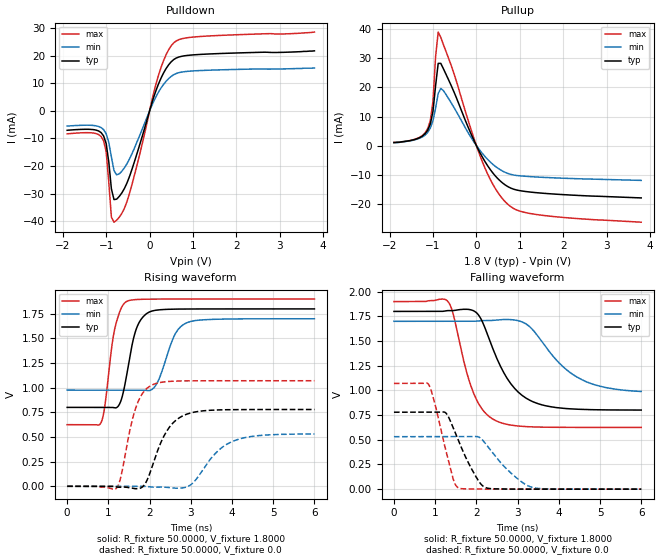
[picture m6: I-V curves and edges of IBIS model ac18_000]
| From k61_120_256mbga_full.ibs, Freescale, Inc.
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|   Model ac18_000
[Model]  ac18_000
Model_type Output
Polarity   Non-Inverting
Enable   Active-High
Vmeas =  0.9000V
Cref =   5.0000pF
Rref =   50.0000
C_comp   2.8000pF   2.5000pF   3.3000pF
[Temperature Range]   25.0000   0.1250k   -40.0000
[Voltage Range]   1.8000V   1.7000V   1.9000V
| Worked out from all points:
|   slope of the pulldown table from 0 to 0.27 V, typ, clamps not added: 22.3 ohm
|   slope of the pullup table from 0 to 0.27 V, typ, clamps not added: 37.5 ohm
|   rising waveform, R_fixture 50.0000, V_fixture 1.8000: 20-80 % time 294ps typ, 374ps min, 247ps max; typ from 0.801 V to 1.8 V
|   rising waveform, R_fixture 50.0000, V_fixture 0.0: 20-80 % time 500ps typ, 675ps min, 357ps max; typ from 0 V to 0.779 V
|   falling waveform, R_fixture 50.0000, V_fixture 1.8000: 20-80 % time 734ps typ, 980ps min, 526ps max; typ from 1.8 V to 0.801 V
|   falling waveform, R_fixture 50.0000, V_fixture 0.0: 20-80 % time 514ps typ, 712ps min, 368ps max; typ from 0.779 V to 0 V
[Pulldown]
|Voltage   I(typ)   I(min)   I(max)
-1.9V     -7.024mA   -5.499mA   -8.317mA
-1.3V     -6.77mA    -5.264mA   -8.01mA
-1.06V    -9.044mA   -6.767mA   -10.8mA
-1V       -11.87mA   -8.293mA   -14.84mA
-880mV    -28.28mA   -16.74mA   -38.55mA
-820mV    -32.16mA   -21.62mA   -40.36mA
-700mV    -31.05mA   -22.85mA   -38.59mA
-520mV    -26.11mA   -19.13mA   -32.84mA
200mV     9.554mA    6.678mA    12.65mA
380mV     15.35mA    10.75mA    20.37mA
560mV     18.67mA    13.17mA    24.75mA
3.8V      21.8mA     15.6mA     28.6mA
[Pullup]
|Voltage   I(typ)   I(min)   I(max)
-1.9V     1mA        1mA        1.1mA
-1.36V    2.38mA     2.23mA     2.47mA
-1.12V    5.32mA     4.56mA     5.88mA
-1.06V    7.48mA     6.04mA     8.7mA
-1V       11.81mA    8.569mA    15.23mA
-940mV    20.56mA    12.89mA    30.55mA
-880mV    28.3mA     17.89mA    39.08mA
-760mV    26.45mA    18.92mA    34.77mA
140mV     -4.031mA   -2.77mA    -5.668mA
680mV     -13.73mA   -9.341mA   -19.61mA
1.4V      -16.26mA   -10.85mA   -23.79mA
3.8V      -18.05mA   -12.01mA   -26.41mA
[Ramp]
| variable   typ   min   max
dV/dt_r  0.4676/0.5001n   0.3185/0.6747n   0.6427/0.3574n
dV/dt_f  0.5993/0.7337n   0.4264/0.9804n   0.7648/0.5257n
R_load = 50.0000
[Rising Waveform]
R_fixture= 50.0000
V_fixture= 1.8000
V_fixture_min= 1.7000
V_fixture_max= 1.9000
|time   V(typ)   V(min)   V(max)
0s        800.8mV    975.9mV    625.4mV
824.9ps   800.7mV    975.9mV    648.2mV
1.157ns   795.6mV    975.9mV    1.601V
1.315ns   879.5mV    975.9mV    1.811V
1.462ns   1.171V     975.9mV    1.879V
1.695ns   1.616V     975.9mV    1.896V
2.025ns   1.774V     975.1mV    1.899V
2.612ns   1.798V     1.538V     1.9V
2.896ns   1.799V     1.658V     1.9V
6ns       1.8V       1.7V       1.9V
[Rising Waveform]
R_fixture= 50.0000
V_fixture= 0.0
|time   V(typ)   V(min)   V(max)
0s        4.829nV    510.4nV    1.272nV
1.198ns   -6.88mV    711.6nV    -18.21mV
1.296ns   -9.268mV   1.008uV    81.25mV
1.661ns   -24.86mV   -9.412uV   791.8mV
1.883ns   19.96mV    120.2uV    972.4mV
2.077ns   219mV      -8.996mV   1.032V
2.452ns   583.1mV    -11.75mV   1.063V
2.891ns   730.5mV    -7.938mV   1.07V
4.013ns   777.9mV    455.6mV    1.071V
6ns       779.4mV    530.9mV    1.071V
[Falling Waveform]
R_fixture= 50.0000
V_fixture= 1.8000
V_fixture_min= 1.7000
V_fixture_max= 1.9000
|time   V(typ)   V(min)   V(max)
0s        1.8V       1.7V       1.9V
1.31ns    1.808V     1.7V       1.901V
1.439ns   1.808V     1.7V       1.772V
1.922ns   1.809V     1.7V       983.1mV
2.108ns   1.728V     1.707V     829.7mV
2.438ns   1.383V     1.712V     700.5mV
2.923ns   1.023V     1.713V     643.8mV
3.465ns   869.8mV    1.565V     629.4mV
4.528ns   808.4mV    1.115V     625.6mV
6ns       801.1mV    989.3mV    625.4mV
[Falling Waveform]
R_fixture= 50.0000
V_fixture= 0.0
|time   V(typ)   V(min)   V(max)
0s        779.4mV    531.6mV    1.071V
847ps     779.4mV    531.6mV    1.057V
1.258ns   772.2mV    531.6mV    394.3mV
1.453ns   606mV      531.6mV    81.86mV
1.572ns   486.2mV    531.6mV    11.69mV
1.993ns   124.1mV    533.5mV    1.085mV
2.239ns   13.34mV    451.4mV    440.9uV
2.769ns   1.25mV     190.4mV    71.43uV
3.332ns   284uV      21.04mV    15.57uV
6ns       1.753uV    43.45uV    152.4nV
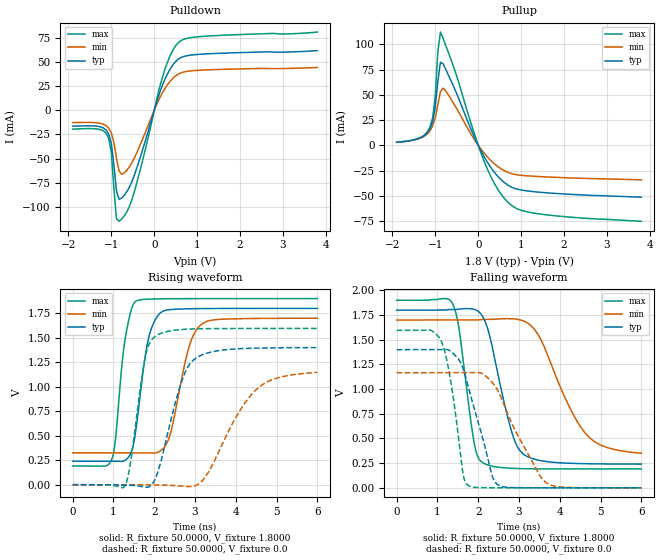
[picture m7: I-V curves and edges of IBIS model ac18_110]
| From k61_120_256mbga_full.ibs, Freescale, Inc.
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|   Model ac18_110
[Model]  ac18_110
Model_type Output
Polarity   Non-Inverting
Enable   Active-High
Vmeas =  0.9000V
Cref =   5.0000pF
Rref =   50.0000
C_comp   2.8000pF   2.5000pF   3.3000pF
[Temperature Range]   25.0000   0.1250k   -40.0000
[Voltage Range]   1.8000V   1.7000V   1.9000V
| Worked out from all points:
|   slope of the pulldown table from 0 to 0.27 V, typ, clamps not added: 7.92 ohm
|   slope of the pullup table from 0 to 0.27 V, typ, clamps not added: 13.2 ohm
|   rising waveform, R_fixture 50.0000, V_fixture 1.8000: 20-80 % time 309ps typ, 423ps min, 248ps max; typ from 0.24 V to 1.8 V
|   rising waveform, R_fixture 50.0000, V_fixture 0.0: 20-80 % time 541ps typ, 919ps min, 314ps max; typ from 0 V to 1.4 V
|   falling waveform, R_fixture 50.0000, V_fixture 1.8000: 20-80 % time 520ps typ, 889ps min, 319ps max; typ from 1.8 V to 0.24 V
|   falling waveform, R_fixture 50.0000, V_fixture 0.0: 20-80 % time 551ps typ, 825ps min, 332ps max; typ from 1.4 V to 0 V
[Pulldown]
|Voltage   I(typ)   I(min)   I(max)
-1.9V     -16.48mA   -12.74mA   -19.56mA
-1.12V    -20.57mA   -16.03mA   -23.92mA
-1.06V    -24.8mA    -18.63mA   -29.33mA
-1V       -34.44mA   -23.65mA   -43.78mA
-880mV    -83.64mA   -49.68mA   -112.2mA
-820mV    -92.06mA   -62.79mA   -114.9mA
-700mV    -88.13mA   -65.03mA   -109.4mA
-520mV    -73.78mA   -54.22mA   -92.52mA
200mV     26.91mA    18.89mA    35.48mA
380mV     43.37mA    30.48mA    57.35mA
560mV     52.89mA    37.37mA    69.96mA
3.8V      61.7mA     44.3mA     80.9mA
[Pullup]
|Voltage   I(typ)   I(min)   I(max)
-1.9V     3mA        3mA        3.1mA
-1.36V    7.2mA      6.83mA     7.38mA
-1.12V    16.73mA    14.49mA    18.27mA
-1.06V    23.85mA    19.35mA    27.54mA
-1V       37.85mA    27.45mA    48.91mA
-940mV    63.31mA    40.19mA    92.94mA
-880mV    82.12mA    53.08mA    112.1mA
-760mV    75.44mA    54.05mA    99.11mA
140mV     -11.48mA   -7.893mA   -16.13mA
680mV     -39.14mA   -26.63mA   -55.88mA
1.4V      -46.38mA   -30.94mA   -67.85mA
3.8V      -51.42mA   -34.22mA   -75.26mA
[Ramp]
| variable   typ   min   max
dV/dt_r  0.8397/0.5407n   0.6884/0.9192n   0.9573/0.3145n
dV/dt_f  0.9357/0.5203n   0.8095/0.8885n   1.0253/0.3193n
R_load = 50.0000
[Rising Waveform]
R_fixture= 50.0000
V_fixture= 1.8000
V_fixture_min= 1.7000
V_fixture_max= 1.9000
|time   V(typ)   V(min)   V(max)
0s        240.2mV    325.7mV    191.2mV
960.6ps   240.2mV    325.7mV    260.9mV
1.277ns   248.1mV    325.7mV    1.466V
1.546ns   547.4mV    325.7mV    1.873V
1.838ns   1.454V     325.9mV    1.894V
2.187ns   1.766V     357.1mV    1.898V
2.402ns   1.788V     531.8mV    1.899V
2.857ns   1.796V     1.413V     1.9V
3.146ns   1.798V     1.633V     1.9V
6ns       1.8V       1.7V       1.9V
[Rising Waveform]
R_fixture= 50.0000
V_fixture= 0.0
|time   V(typ)   V(min)   V(max)
0s        2.118nV    236.1nV    538.6pV
1.279ns   -5.089mV   517.1nV    -12.91mV
1.406ns   -5.164mV   -157.3nV   194.6mV
1.783ns   -25.49mV   136uV      1.314V
2.064ns   101.6mV    -4.2mV     1.525V
2.641ns   1.015V     -13.45mV   1.583V
2.98ns    1.28V      -13.47mV   1.591V
3.321ns   1.347V     121.2mV    1.594V
4.499ns   1.395V     971.3mV    1.595V
6ns       1.399V     1.147V     1.595V
[Falling Waveform]
R_fixture= 50.0000
V_fixture= 1.8000
V_fixture_min= 1.7000
V_fixture_max= 1.9000
|time   V(typ)   V(min)   V(max)
0s        1.8V       1.7V       1.9V
1.378ns   1.806V     1.7V       1.861V
1.542ns   1.812V     1.7V       1.58V
1.903ns   1.808V     1.7V       448.7mV
2.103ns   1.74V      1.705V     256.8mV
2.821ns   566.3mV    1.713V     197.9mV
3.072ns   354.1mV    1.696V     194.5mV
3.491ns   279mV      1.537V     192.3mV
4.612ns   244.4mV    560.2mV    191.2mV
6ns       240.5mV    350.8mV    191.2mV
[Falling Waveform]
R_fixture= 50.0000
V_fixture= 0.0
|time   V(typ)   V(min)   V(max)
0s        1.4V       1.166V     1.595V
825.2ps   1.4V       1.166V     1.597V
1.087ns   1.4V       1.166V     1.492V
1.333ns   1.38V      1.166V     1.061V
1.638ns   1.198V     1.166V     120.3mV
1.753ns   1.029V     1.166V     24.2mV
2.332ns   138.4mV    1.073V     1.018mV
2.484ns   30.21mV    983.5mV    678.7uV
3.66ns    503.7uV    53.85mV    26.56uV
6ns       4.855uV    232.4uV    -89.94nV
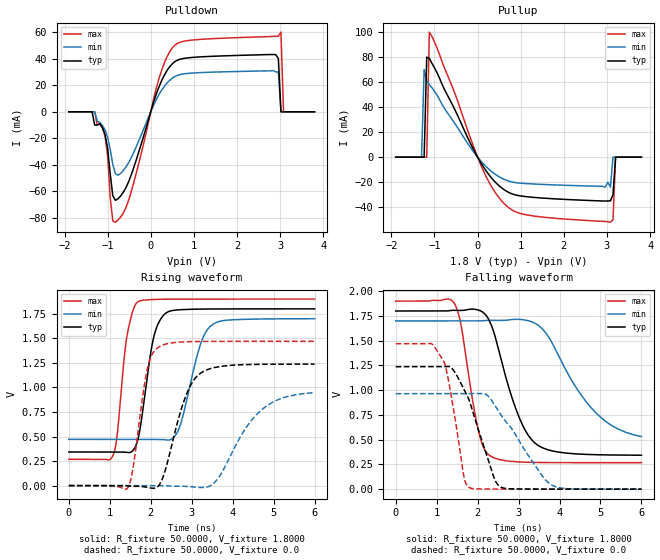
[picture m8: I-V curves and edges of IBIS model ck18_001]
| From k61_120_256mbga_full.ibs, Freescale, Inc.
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|   Model ck18_001
[Model]  ck18_001
Model_type Output
Polarity   Non-Inverting
Enable   Active-High
Vmeas =  0.9000V
Cref =   5.0000pF
Rref =   50.0000
C_comp   2.8000pF   2.5000pF   3.3000pF
[Temperature Range]   25.0000   0.1250k   -40.0000
[Voltage Range]   1.8000V   1.7000V   1.9000V
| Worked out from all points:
|   slope of the pulldown table from 0 to 0.27 V, typ, clamps not added: 11 ohm
|   slope of the pullup table from 0 to 0.27 V, typ, clamps not added: 18.7 ohm
|   rising waveform, R_fixture 50.0000, V_fixture 1.8000: 20-80 % time 310ps typ, 437ps min, 241ps max; typ from 0.342 V to 1.8 V
|   rising waveform, R_fixture 50.0000, V_fixture 0.0: 20-80 % time 520ps typ, 861ps min, 301ps max; typ from 0 V to 1.24 V
|   falling waveform, R_fixture 50.0000, V_fixture 1.8000: 20-80 % time 663ps typ, 1.07ns min, 387ps max; typ from 1.8 V to 0.343 V
|   falling waveform, R_fixture 50.0000, V_fixture 0.0: 20-80 % time 607ps typ, 947ps min, 349ps max; typ from 1.24 V to 0 V
[Pulldown]
|Voltage   I(typ)   I(min)   I(max)
-1.9V     0A         0A         0A
-1.12V    -11.9mA    -10.3mA    -12.1mA
-880mV    -63.24mA   -39.62mA   -82.32mA
-820mV    -66.65mA   -46.58mA   -83.13mA
-460mV    -48.21mA   -35.12mA   -61.03mA
260mV     23.94mA    16.63mA    31.94mA
620mV     38.85mA    27.44mA    51.51mA
2.9V      43mA       30mA       56.81mA
2.96V     40mA       30mA       56.9mA
3.02V     0A         0A         60mA
3.08V     0A         0A         0A
3.8V      0A         0A         0A
[Pullup]
|Voltage   I(typ)   I(min)   I(max)
-1.9V     0A         0A         0A
-1.3V     0A         0A         0A
-1.24V    0A         70mA       0A
-1.18V    80mA       61mA       0A
-1.12V    79mA       58mA       100mA
140mV     -8.076mA   -5.542mA   -11.38mA
440mV     -21.05mA   -14.4mA    -29.84mA
800mV     -29.37mA   -19.87mA   -42.24mA
3.08V     -35mA      -24mA      -52mA
3.14V     -30mA      0A         -50mA
3.2V      0A         0A         0A
3.8V      0A         0A         0A
[Ramp]
| variable   typ   min   max
dV/dt_r  0.7423/0.5199n   0.5683/0.8572n   0.8815/0.3011n
dV/dt_f  0.8741/0.6631n   0.7011/1.0687n   0.9794/0.3868n
R_load = 50.0000
[Rising Waveform]
R_fixture= 50.0000
V_fixture= 1.8000
V_fixture_min= 1.7000
V_fixture_max= 1.9000
|time   V(typ)   V(min)   V(max)
0s        342.5mV    471.1mV    267.7mV
1.081ns   342.7mV    471.1mV    309.3mV
1.182ns   342.5mV    471.1mV    519.5mV
1.418ns   339mV      471.1mV    1.518V
1.692ns   479.1mV    471mV      1.873V
2.066ns   1.5V       470.6mV    1.896V
2.36ns    1.754V     466.5mV    1.899V
2.691ns   1.79V      581.5mV    1.9V
3.452ns   1.799V     1.622V     1.9V
6ns       1.8V       1.7V       1.9V
[Rising Waveform]
R_fixture= 50.0000
V_fixture= 0.0
|time   V(typ)   V(min)   V(max)
0s        3.771nV    301.5nV    1.569nV
1.44ns    -2.392mV   379.6nV    -22.42mV
1.572ns   -6.559mV   -2.491uV   189.7mV
1.921ns   -18.86mV   165.7uV    1.196V
2.203ns   4.92mV     203uV      1.413V
2.817ns   868.7mV    -6.762mV   1.464V
3.175ns   1.132V     -18.38mV   1.468V
3.625ns   1.208V     63.15mV    1.469V
4.711ns   1.235V     774mV      1.469V
6ns       1.237V     947.2mV    1.469V
[Falling Waveform]
R_fixture= 50.0000
V_fixture= 1.8000
V_fixture_min= 1.7000
V_fixture_max= 1.9000
|time   V(typ)   V(min)   V(max)
0s        1.8V       1.7V       1.9V
1.428ns   1.807V     1.7V       1.879V
1.598ns   1.806V     1.7V       1.651V
2.017ns   1.81V      1.7V       593.9mV
2.296ns   1.694V     1.706V     340.1mV
2.945ns   798.8mV    1.716V     276.9mV
3.376ns   474.7mV    1.681V     270.5mV
3.726ns   397.1mV    1.542V     268.8mV
4.79ns    349.2mV    814.2mV    267.8mV
6ns       343.2mV    531.6mV    267.7mV
[Falling Waveform]
R_fixture= 50.0000
V_fixture= 0.0
|time   V(typ)   V(min)   V(max)
0s        1.237V     964.5mV    1.469V
867.7ps   1.237V     964.5mV    1.471V
1.171ns   1.237V     964.5mV    1.293V
1.346ns   1.231V     964.5mV    966.9mV
1.661ns   1.014V     964.5mV    136.7mV
1.788ns   903.8mV    964.4mV    17.89mV
2.209ns   363mV      956.2mV    1.55mV
2.573ns   19.96mV    746.8mV    538.7uV
3.829ns   384.3uV    37.09mV    15.42uV
6ns       5.318uV    257.6uV    137.3nV
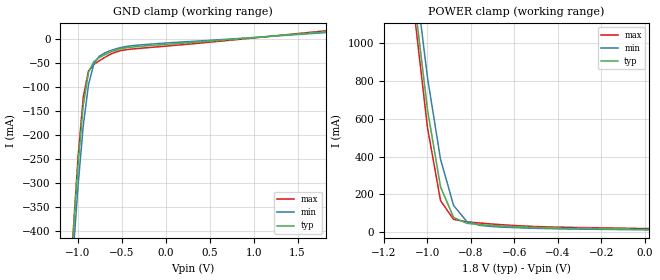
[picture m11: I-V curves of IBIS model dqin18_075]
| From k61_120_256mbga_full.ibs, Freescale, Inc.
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|   Model dqin18_075
[Model]  dqin18_075
Model_type Input
Polarity   Non-Inverting
Enable   Active-High
Vinl =   0.6500V
Vinh =   1.1500V
C_comp   2.8000pF   2.5000pF   3.3000pF
[Temperature Range]   25.0000   0.1250k   -40.0000
[Voltage Range]   1.8000V   1.7000V   1.9000V
[GND_clamp]
|Voltage   I(typ)   I(min)   I(max)
-1.9V     -3.347A    -3.309A    -3.39A
-1.06V    -423.3mA   -460.8mA   -415.6mA
-1V       -261.9mA   -306.4mA   -246.5mA
-940mV    -136.6mA   -179.7mA   -119.9mA
-880mV    -68.17mA   -93.77mA   -65.55mA
-820mV    -46.26mA   -51.36mA   -52.39mA
-760mV    -38.06mA   -35.43mA   -44.75mA
-700mV    -32.12mA   -28.44mA   -37.89mA
-580mV    -22.77mA   -20.1mA    -26.91mA
-460mV    -17.48mA   -14.88mA   -21.58mA
-40mV     -10.65mA   -7.909mA   -14.56mA
1.82V     16.33mA    14.42mA    18.19mA
[POWER_clamp]
|Voltage   I(typ)   I(min)   I(max)
-1.9V     11.96A     11.9A      12.05A
-1.06V    1.229A     1.381A     1.153A
-1V       648.6mA    818.8mA    553.3mA
-940mV    240.1mA    386.1mA    167.3mA
-880mV    78.59mA    142.1mA    68.24mA
-820mV    47.93mA    57.78mA    55.38mA
-760mV    40.35mA    36.51mA    48.98mA
-640mV    31.81mA    26.33mA    38.56mA
-460mV    23.84mA    19.71mA    28.77mA
20mV      15.71mA    12.66mA    19.29mA
